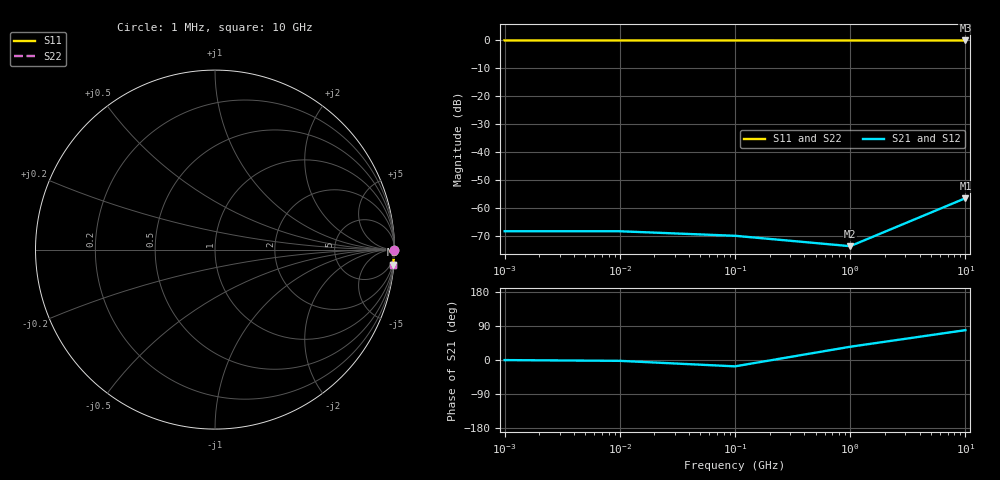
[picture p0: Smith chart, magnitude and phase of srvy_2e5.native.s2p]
! Sonnet Data File
! From: em Version : 18.53-Lite
! From Project: d_s6_2e5
! Data is NOT De-embedded
! Data File Written: 10/12/2026 11:28:05
!< HDATE 10/12/2026 11:28:05
!< MDATE 10/12/2026 11:28:05
# GHZ S RI R 50.00000
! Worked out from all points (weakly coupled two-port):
!   5 points, 1 MHz to 10 GHz, reference 50 ohm
!   highest |S21| = -56.54 dB at 10 GHz (marker M1); lowest = -73.7 dB at 1 GHz (marker M2)
!   lowest |S11| = 0.0 dB at 10 GHz (marker M3), VSWR 719.28, Z = 39.3 - j1.19e+03 ohm
!   |S11| at or under -10 dB: nowhere
!   |S22| runs from 0.0 to 0.0 dB; largest |S21 - S12| = 3e-11
0.001  0.9986 -1.55e-05  0.000382 -1.5e-06  0.000382 -1.5e-06  0.9986 -1.55e-05
0.01  0.9986 -0.000155  0.00038 -1.49e-05  0.00038 -1.49e-05  0.9986 -0.000155
0.1  0.9983 -0.00135  0.000302 -9.1e-05  0.000302 -9.1e-05  0.9983 -0.00135
1  0.9973 -0.00864  0.000169 0.000118  0.000169 0.000118  0.9973 -0.00864
10  0.9937 -0.0838  0.00029 0.00146  0.00029 0.00146  0.9937 -0.0838
